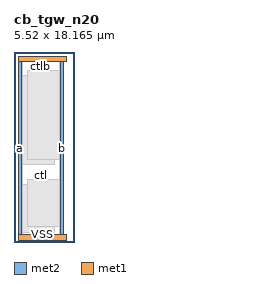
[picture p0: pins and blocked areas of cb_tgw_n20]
MACRO cb_tgw_n20
  CLASS BLOCK ;
  ORIGIN 0.000 0.000 ;
  SIZE 5.520 BY 18.165 ;
  SYMMETRY X Y ;
  PIN a
    DIRECTION INOUT ;
    USE SIGNAL ;
    PORT
      LAYER met2 ;
        RECT 0.455 0.435 0.755 17.505 ;
    END
  END a
  PIN b
    DIRECTION INOUT ;
    USE SIGNAL ;
    PORT
      LAYER met2 ;
        RECT 4.405 0.435 4.705 17.505 ;
    END
  END b
  PIN ctl
    DIRECTION INOUT ;
    USE SIGNAL ;
    PORT
      LAYER met1 ;
        RECT 2.410 6.145 2.750 6.485 ;
    END
  END ctl
  PIN ctlb
    DIRECTION INOUT ;
    USE SIGNAL ;
    PORT
      LAYER met1 ;
        RECT 2.410 16.605 2.750 16.945 ;
    END
  END ctlb
  PIN VSS
    DIRECTION INOUT ;
    USE GROUND ;
    PORT
      LAYER met1 ;
        RECT 0.460 0.185 5.060 0.685 ;
    END
  END VSS
  PIN VDD
    DIRECTION INOUT ;
    USE POWER ;
    PORT
      LAYER met1 ;
        RECT 0.460 17.255 5.060 17.755 ;
    END
  END VDD
  OBS
    LAYER met1 ;
      RECT 0.460 0.185 5.060 0.685 ;
      RECT 0.440 0.925 3.880 5.455 ;
      RECT 1.280 1.455 4.720 5.965 ;
      RECT 2.410 6.145 2.750 6.485 ;
      RECT 0.440 7.385 3.880 15.915 ;
      RECT 1.280 7.915 4.720 16.425 ;
      RECT 2.410 16.605 2.750 16.945 ;
      RECT 0.460 17.255 5.060 17.755 ;
    LAYER met2 ;
      RECT 0.440 0.435 0.770 17.505 ;
      RECT 4.390 0.435 4.720 17.505 ;
  END
END cb_tgw_n20
